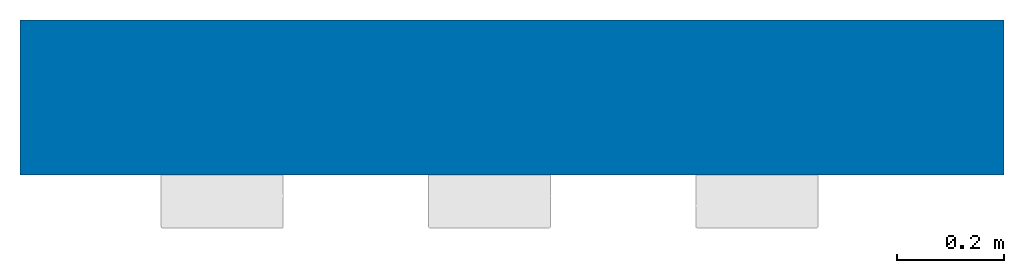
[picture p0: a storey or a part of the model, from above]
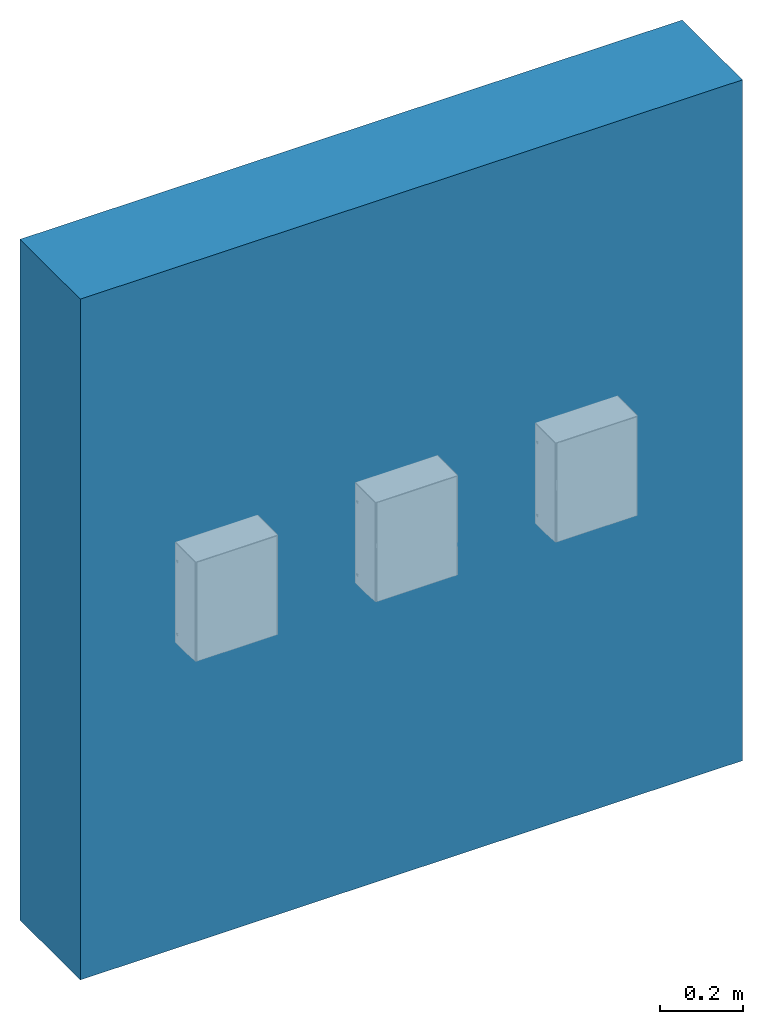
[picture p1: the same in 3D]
Properties of the parts of a building model (IFC2X3)

# File
Description: ViewDefinition [CoordinationView_V2.0]
File name: Project Number
Time: 2021-06-11T09:09:53
Written by: The EXPRESS Data Manager Version 5.02.0100.07 : 28 Aug 2013
Made in: 20170223_1515(x64) - Exporter 18.0.0.420 - Alternate UI 18.0.0.420
Comment: STEP Physical File produced by: The EXPRESS Data Manager Version 5.02.0100.07 : 28 Aug 2013 * Module: EDMstepFileFactory/EDMstandAlone * Creation date: Fri Jun 11 09:09:53 2021 * Host: DESKTOP-KN3O7NT * Database: C:\Users\SARAHS~1\AppData\Local\Temp\{A3614A68-85B3-4881-87CC-31234E6E36D7}\ifc * Database version: 5507 * Database creation date: Fri Jun 11 09:09:50 2021 * Schema: IFC2X3 * Model: DataRepository.ifc * Model creation date: Fri Jun 11 09:09:50 2021 * Header model: DataRepository.ifc_HeaderModel * Header model creation date: Fri Jun 11 09:09:50 2021 * EDMuser: sdai-user * EDMgroup: sdai-group * License ID and type: 5605 : Permanent license. Expiry date: * EDMstepFileFactory options: 020000

# IfcProject, Project Number
LongName: Project Name; Phase: Project Status

# IfcSite, Default
RefLatitude: 51, 30, 23, 112487; RefLongitude: 0, -7, -37, -956022; RefElevation: 0 mm

# IfcBuilding
Pset_BuildingCommon - NumberOfStoreys: 1

# IfcBuildingStorey, Level 0
LongName: Level 0; Elevation: 0 mm

# IfcBuildingElementProxy: Brushed Stainless Steel, Duten_HndDriers_M490:Brushed Stainless Steel:311412
In: Level 0
Type - PredefinedType: USERDEFINED; Classification: E2020200 Furniture & Accessories (Uniformat); Material: Duten_Metal_BrushedStainlessSteel
Pset_BuildingElementProxyCommon - Reference: n/a
Pset_ManufacturerTypeInformation - ModelReference: Brushed Stainless Steel; Manufacturer: Duten

# IfcBuildingElementProxy: Chromed Brass, Duten_HndDriers_M490:Chromed Brass:320191
In: Level 0
Type - PredefinedType: USERDEFINED; Classification: E2020200 Furniture & Accessories (Uniformat); Material: Duten_Metal_Chrome
Pset_BuildingElementProxyCommon - Reference: n/a
Pset_ManufacturerTypeInformation - ModelReference: Chromed Brass; Manufacturer: Duten

# IfcBuildingElementProxy: Matte Black, Duten_HndDriers_M490:Matte Black:320219
In: Level 0
Type - PredefinedType: USERDEFINED; Classification: E2020200 Furniture & Accessories (Uniformat); Material: Duten_Metal_MatteBlack
Pset_BuildingElementProxyCommon - Reference: n/a
Pset_ManufacturerTypeInformation - ModelReference: Matte Black; Manufacturer: Duten

# IfcWallStandardCase: Basic Wall:Wall-Ext_102Bwk-75Ins-100LBlk-12P, Basic Wall:Wall-Ext_102Bwk-75Ins-100LBlk-12P:310497
In: Level 0
Type - PredefinedType: STANDARD; Material: Brick, Common 102.5 mm, Fiberglass Batt 75 mm, Concrete Masonry Units _Low Density 100 mm, Plaster 12.5 mm
Pset_WallCommon - Reference: Wall-Ext_102Bwk-75Ins-100LBlk-12P; LoadBearing: no; ExtendToStructure: no; IsExternal: yes; ThermalTransmittance: 0.235926 kg/K/s3
